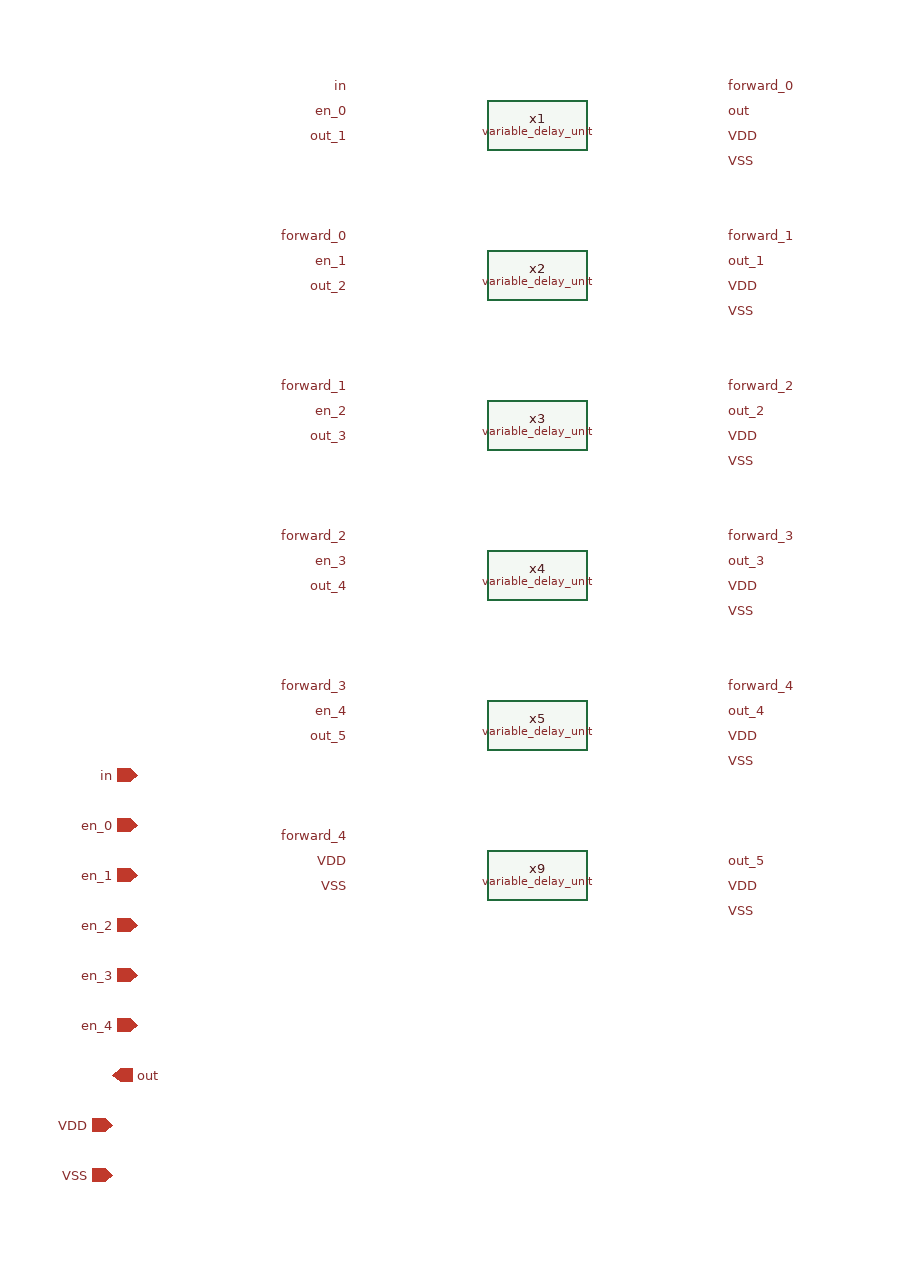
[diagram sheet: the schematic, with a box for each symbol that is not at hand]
v {xschem version=3.4.5 file_version=1.2
}
G {}
K {}
V {}
S {}
E {}
C {devices/iopin.sym} 70 -80 0 0 {name=p1 lab=VDD}
C {devices/ipin.sym} 90 -360 0 0 {name=p3 lab=in}
C {devices/opin.sym} 70 -120 0 0 {name=p5 lab=out}
C {devices/iopin.sym} 70 -40 0 0 {name=p2 lab=VSS}
C {devices/ipin.sym} 90 -320 0 0 {name=p13 lab=en_0}
C {variable_delay_unit.sym} 410 -880 0 0 {name=x1}
C {devices/lab_pin.sym} 560 -870 0 1 {name=p10 sig_type=std_logic lab=VDD}
C {devices/lab_pin.sym} 560 -850 0 1 {name=p4 sig_type=std_logic lab=VSS}
C {devices/lab_pin.sym} 260 -890 0 0 {name=p6 sig_type=std_logic lab=en_0}
C {devices/lab_pin.sym} 560 -890 0 1 {name=p7 sig_type=std_logic lab=out}
C {devices/lab_pin.sym} 260 -910 0 0 {name=p8 sig_type=std_logic lab=in}
C {variable_delay_unit.sym} 410 -760 0 0 {name=x2}
C {devices/lab_pin.sym} 560 -750 0 1 {name=p9 sig_type=std_logic lab=VDD}
C {devices/lab_pin.sym} 560 -730 0 1 {name=p11 sig_type=std_logic lab=VSS}
C {devices/lab_pin.sym} 260 -770 0 0 {name=p12 sig_type=std_logic lab=en_1}
C {devices/lab_pin.sym} 560 -770 0 1 {name=p14 sig_type=std_logic lab=out_1}
C {devices/lab_pin.sym} 560 -910 0 1 {name=p16 sig_type=std_logic lab=forward_0}
C {devices/lab_pin.sym} 260 -790 0 0 {name=p15 sig_type=std_logic lab=forward_0}
C {devices/ipin.sym} 90 -280 0 0 {name=p17 lab=en_1}
C {devices/lab_pin.sym} 260 -870 0 0 {name=p18 sig_type=std_logic lab=out_1}
C {devices/lab_pin.sym} 560 -790 0 1 {name=p19 sig_type=std_logic lab=forward_1}
C {variable_delay_unit.sym} 410 -640 0 0 {name=x3}
C {devices/lab_pin.sym} 560 -630 0 1 {name=p20 sig_type=std_logic lab=VDD}
C {devices/lab_pin.sym} 560 -610 0 1 {name=p21 sig_type=std_logic lab=VSS}
C {devices/lab_pin.sym} 260 -650 0 0 {name=p22 sig_type=std_logic lab=en_2}
C {devices/lab_pin.sym} 560 -650 0 1 {name=p23 sig_type=std_logic lab=out_2}
C {devices/lab_pin.sym} 260 -670 0 0 {name=p24 sig_type=std_logic lab=forward_1}
C {devices/lab_pin.sym} 560 -670 0 1 {name=p25 sig_type=std_logic lab=forward_2}
C {devices/lab_pin.sym} 260 -750 0 0 {name=p26 sig_type=std_logic lab=out_2}
C {variable_delay_unit.sym} 410 -520 0 0 {name=x4}
C {devices/lab_pin.sym} 560 -510 0 1 {name=p27 sig_type=std_logic lab=VDD}
C {devices/lab_pin.sym} 560 -490 0 1 {name=p28 sig_type=std_logic lab=VSS}
C {devices/lab_pin.sym} 260 -530 0 0 {name=p29 sig_type=std_logic lab=en_3}
C {devices/lab_pin.sym} 560 -530 0 1 {name=p30 sig_type=std_logic lab=out_3}
C {devices/lab_pin.sym} 260 -550 0 0 {name=p31 sig_type=std_logic lab=forward_2}
C {devices/lab_pin.sym} 560 -550 0 1 {name=p32 sig_type=std_logic lab=forward_3}
C {devices/lab_pin.sym} 260 -630 0 0 {name=p33 sig_type=std_logic lab=out_3}
C {devices/lab_pin.sym} 260 -510 0 0 {name=p40 sig_type=std_logic lab=out_4}
C {devices/ipin.sym} 90 -240 0 0 {name=p62 lab=en_2}
C {variable_delay_unit.sym} 410 -280 0 0 {name=x9}
C {devices/lab_pin.sym} 560 -270 0 1 {name=p68 sig_type=std_logic lab=VDD}
C {devices/lab_pin.sym} 560 -250 0 1 {name=p69 sig_type=std_logic lab=VSS}
C {devices/lab_pin.sym} 560 -290 0 1 {name=p71 sig_type=std_logic lab=out_5}
C {devices/lab_pin.sym} 260 -310 0 0 {name=p72 sig_type=std_logic lab=forward_4}
C {devices/lab_pin.sym} 260 -290 0 0 {name=p70 sig_type=std_logic lab=VDD}
C {devices/lab_pin.sym} 260 -270 0 0 {name=p75 sig_type=std_logic lab=VSS}
C {devices/ipin.sym} 90 -200 0 0 {name=p63 lab=en_3}
C {variable_delay_unit.sym} 410 -400 0 0 {name=x5}
C {devices/lab_pin.sym} 560 -390 0 1 {name=p34 sig_type=std_logic lab=VDD}
C {devices/lab_pin.sym} 560 -370 0 1 {name=p35 sig_type=std_logic lab=VSS}
C {devices/lab_pin.sym} 260 -410 0 0 {name=p36 sig_type=std_logic lab=en_4}
C {devices/lab_pin.sym} 560 -410 0 1 {name=p37 sig_type=std_logic lab=out_4}
C {devices/lab_pin.sym} 260 -430 0 0 {name=p38 sig_type=std_logic lab=forward_3}
C {devices/lab_pin.sym} 560 -430 0 1 {name=p39 sig_type=std_logic lab=forward_4}
C {devices/lab_pin.sym} 260 -390 0 0 {name=p41 sig_type=std_logic lab=out_5}
C {devices/ipin.sym} 90 -160 0 0 {name=p42 lab=en_4}
